VERSION 5.8 ;
BUSBITCHARS "[]" ;
DIVIDERCHAR "/" ;
UNITS
  DATABASE MICRONS 2000 ;
END UNITS
MANUFACTURINGGRID 0.005 ;
SITE unit
  SIZE 1.0 BY 1.0 ;
  CLASS CORE ;
  SYMMETRY Y ;
END unit
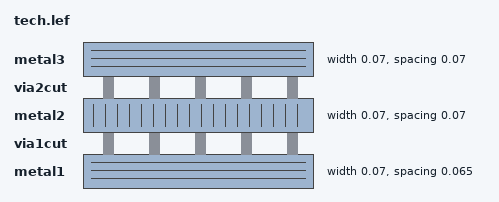
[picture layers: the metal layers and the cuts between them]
LAYER metal1
  TYPE ROUTING ;
  SPACING 0.065 ;
  WIDTH 0.07 ;
  DIRECTION HORIZONTAL ;
  RESISTANCE RPERSQ 0.10 ;
  CAPACITANCE CPERSQDIST 0.0002 ;
END metal1
LAYER via1cut
  TYPE CUT ;
END via1cut
LAYER metal2
  TYPE ROUTING ;
  SPACING 0.07 ;
  WIDTH 0.07 ;
  DIRECTION VERTICAL ;
  RESISTANCE RPERSQ 0.10 ;
  CAPACITANCE CPERSQDIST 0.0002 ;
END metal2
LAYER via2cut
  TYPE CUT ;
END via2cut
LAYER metal3
  TYPE ROUTING ;
  SPACING 0.07 ;
  WIDTH 0.07 ;
  DIRECTION HORIZONTAL ;
  RESISTANCE RPERSQ 0.10 ;
  CAPACITANCE CPERSQDIST 0.0002 ;
END metal3
VIA via1 DEFAULT
  RESISTANCE 1.0 ;
  LAYER metal1 ;
    RECT -0.05 -0.05 0.05 0.05 ;
  LAYER via1cut ;
    RECT -0.035 -0.035 0.035 0.035 ;
  LAYER metal2 ;
    RECT -0.05 -0.05 0.05 0.05 ;
END via1
VIA via2 DEFAULT
  RESISTANCE 1.0 ;
  LAYER metal2 ;
    RECT -0.05 -0.05 0.05 0.05 ;
  LAYER via2cut ;
    RECT -0.035 -0.035 0.035 0.035 ;
  LAYER metal3 ;
    RECT -0.05 -0.05 0.05 0.05 ;
END via2
END LIBRARY
